//AI Generated AMUX2_3V.lef

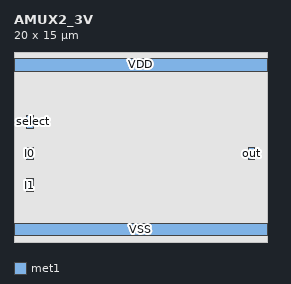
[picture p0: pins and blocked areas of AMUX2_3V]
MACRO AMUX2_3V
  CLASS CORE ;
  SITE unithddbl ;
  ORIGIN 0.000 0.000 ;
  FOREIGN AMUX2_3V 0.000 0.000 ;
  SIZE 20.000 BY 15.000 ;
  SYMMETRY X Y ;

  PIN I0
    DIRECTION INPUT ;
    USE SIGNAL ;
    PORT
      LAYER met1 ;
        RECT 1.000 6.500 1.500 7.500 ;
    END
  END I0

  PIN I1
    DIRECTION INPUT ;
    USE SIGNAL ;
    PORT
      LAYER met1 ;
        RECT 1.000 4.000 1.500 5.000 ;
    END
  END I1

  PIN select
    DIRECTION INPUT ;
    USE SIGNAL ;
    PORT
      LAYER met1 ;
        RECT 1.000 9.000 1.500 10.000 ;
    END
  END select

  PIN out
    DIRECTION OUTPUT ;
    USE SIGNAL ;
    PORT
      LAYER met1 ;
        RECT 18.500 6.500 19.000 7.500 ;
    END
  END out

  PIN VDD
    DIRECTION INOUT ;
    USE POWER ;
    SHAPE ABUTMENT ;
    PORT
      LAYER met1 ;
        RECT 0.000 13.500 20.000 14.500 ;
    END
  END VDD

  PIN VSS
    DIRECTION INOUT ;
    USE GROUND ;
    SHAPE ABUTMENT ;
    PORT
      LAYER met1 ;
        RECT 0.000 0.500 20.000 1.500 ;
    END
  END VSS

  OBS
    LAYER met1 ;
      RECT 0.000 0.000 20.000 15.000 ;
  END

END AMUX2_3V
